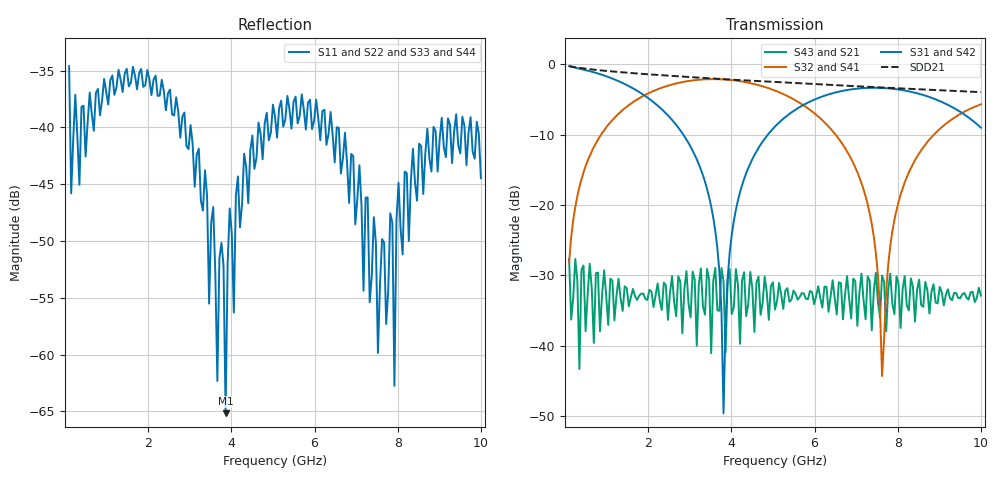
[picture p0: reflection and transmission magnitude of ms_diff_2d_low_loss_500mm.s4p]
! Variables:
!  s = 0.5mm
!  t = 50um
!  w = 0.35mm
!  x_sub = 3mm
!  z_air = 1mm
!  z_sub = 0.2104mm
# GHZ S MA R 50.000000
! Terminal data exported
! Port[1] = left_A
! Port[2] = right_A
! Port[3] = left_B
! Port[4] = right_B
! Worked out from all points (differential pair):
!   201 points, 100 MHz to 10 GHz, reference 50 ohm
!   strongest paths, dB at 100 MHz, 2.575 GHz, 5.05 GHz, 7.525 GHz, 10 GHz:
!     S31: -0.3, -7.9, -8.9, -3.4, -9.0
!     S42: -0.3, -7.9, -8.9, -3.4, -9.0
!     S32: -28.1, -2.9, -3.8, -30.0, -5.7
!     S41: -28.1, -2.9, -3.8, -30.0, -5.7
!     S43: -27.7, -30.1, -34.8, -33.8, -32.9
!     S21: -27.7, -30.1, -34.8, -33.8, -32.9
!   taken as a pair (ports 1,2 in; 3,4 out), SDD21 dB: -0.3, -1.7, -2.5, -3.3, -4.0
!   lowest |S11| = -65.2 dB at 3.862 GHz (marker M1), VSWR 1.00, Z = 49.9 + j0.00954 ohm
!   |S11| at or under -10 dB: start of sweep to end of sweep
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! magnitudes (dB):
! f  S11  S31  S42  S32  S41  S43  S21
! 100 MHz  -34.6  -0.3  -0.3  -28.1  -28.1  -27.7  -27.7
! 3.021 GHz  -39.8  -11.7  -11.7  -2.4  -2.4  -36.0  -36.0
! 3.862 GHz  -65.2  -36.7  -36.6  -2.2  -2.2  -40.9  -40.9
! 5 GHz  -38.0  -9.2  -9.2  -3.6  -3.6  -31.0  -31.0
! 7.08 GHz  -43.3  -3.5  -3.5  -16.1  -16.1  -32.5  -32.5
! 7.624 GHz  -49.8  -3.4  -3.4  -44.3  -44.3  -30.0  -30.0
! 10 GHz  -44.5  -9.0  -9.0  -5.7  -5.7  -32.9  -32.9
